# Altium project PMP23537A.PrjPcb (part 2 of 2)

## Sheet PMP23537A_PFC.SchDoc
size 431 x 279 mm; Date: Not shown in title block; ApprovedBy: Not shown in title block; CheckedBy: Not shown in title block; Author: Not shown in title block; CompanyName: Not shown in title block; Engineer: Not shown in title block; Organization: Not shown in title block; Address1: Not shown in title block; Address2: Not shown in title block; Address3: Not shown in title block; Address4: Not shown in title block; DocumentNumber: 1; Revision: Use project parameter SCH_Rev; SheetNumber: 1; SheetTotal: 2; PageSetup: Record=PageOptions¦CenterHorizontal=True¦CenterVertical=True¦PrintScale=1.00¦XCorrection=1.00¦YCorrection=1.00¦PrintKind=0¦BorderSize=5000000¦LeftOffset=0¦BottomOffset=0¦Orientation=2¦PaperLength=1000¦PaperWidth=1000¦Scale=100¦PaperSource=15¦PrintQuality=600¦MediaType=1¦DitherType=10¦PaperKind=Letter¦PrintScaleMode=1

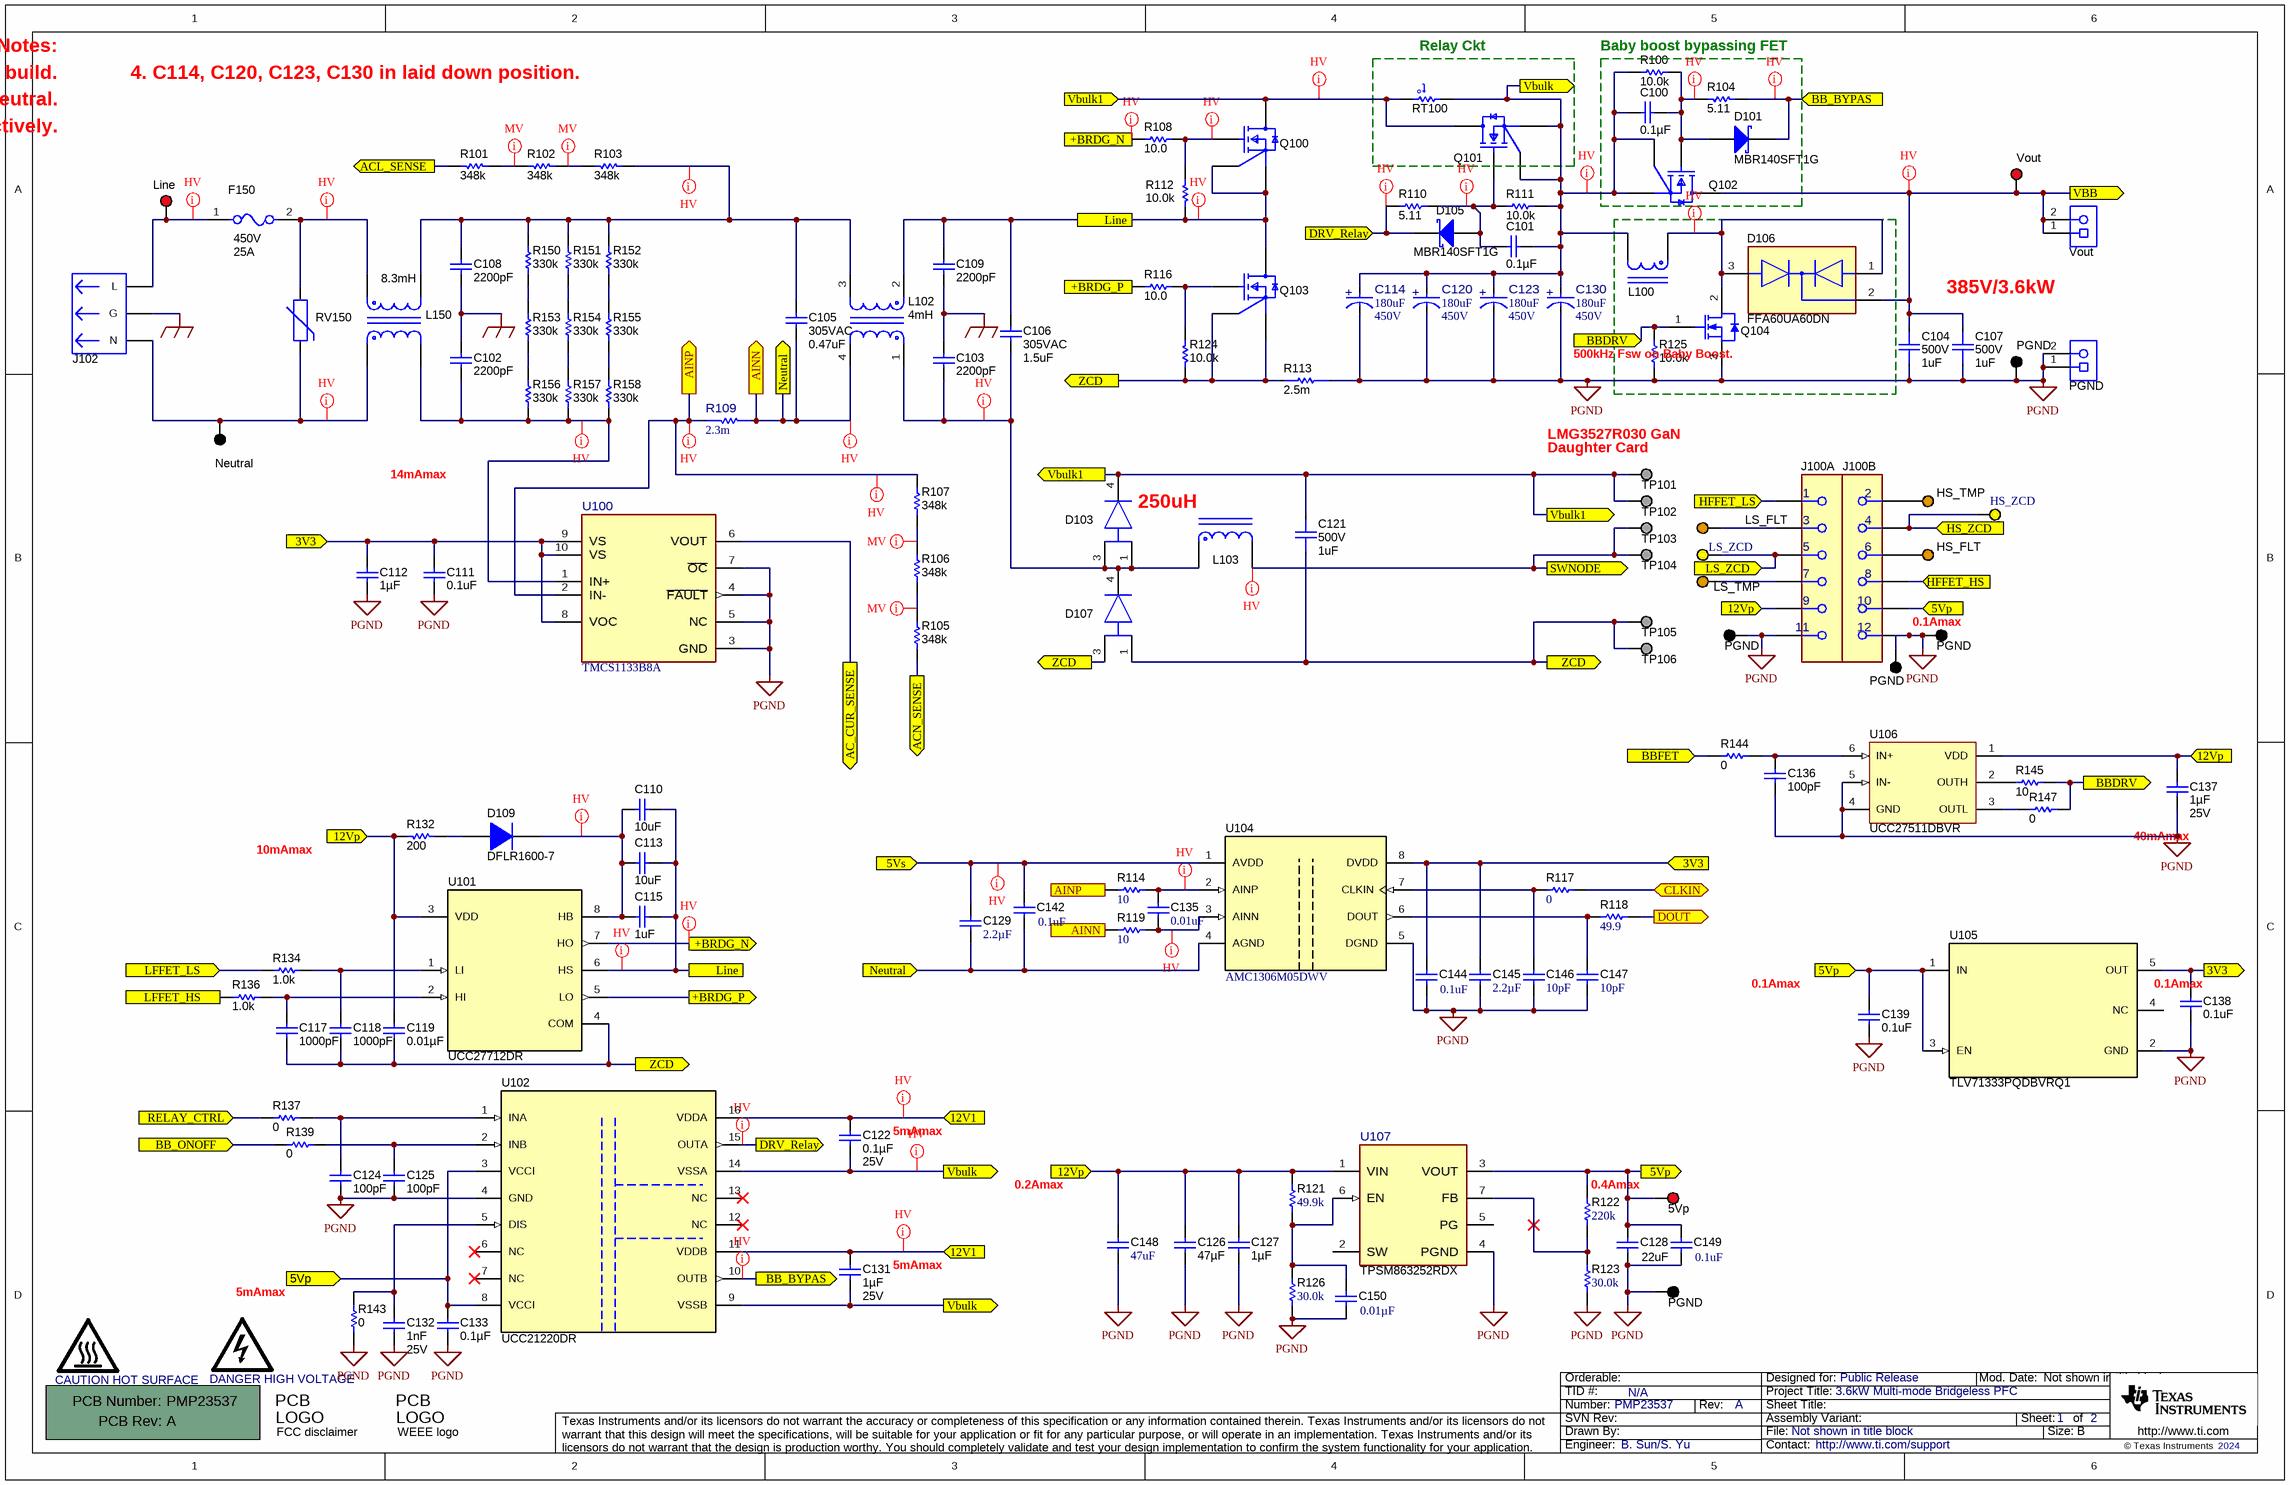
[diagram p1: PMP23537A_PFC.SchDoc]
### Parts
(Parts that share a designator on the sheet are numbered #1, #2 ... from top to bottom, then left to right.)
5Vp  5000  [Keystone5000]  (value not drawn)
!PCB100  Printed Circuit Board  (value not drawn)  (mechanical)
C100  ValueDisplayed: 0.1µF  [0603]  (hidden comment: 06033C104JAT2A)
C101  ValueDisplayed: 0.1µF  [0603]  (hidden comment: 06033C104JAT2A)
C102  ValueDisplayed: 2200pF  [E_900x700x900]  (hidden comment: DE6E3KJ222MN3A)
C103  ValueDisplayed: 2200pF  [E_900x700x900]  (hidden comment: DE6E3KJ222MN3A)
C104  VDC_V: 500V  ValueDisplayed: 1uF  [FP-B58031U5105M062_SMD2-MFG]  (hidden comment: B58031U5105M062)
C105  Value2: 305VAC  ValueDisplayed: 0.47uF  [B32923_16.5mm_10.5]  (hidden comment: B32923H3474K000)
C106  Value2: 305VAC  ValueDisplayed: 1.5uF  [B32923_29.5mm]  (hidden comment: B32923H3155K000)
C107  VDC_V: 500V  ValueDisplayed: 1uF  [FP-B58031U5105M062_SMD2-MFG]  (hidden comment: B58031U5105M062)
C108  ValueDisplayed: 2200pF  [E_900x700x900]  (hidden comment: DE6E3KJ222MN3A)
C109  ValueDisplayed: 2200pF  [E_900x700x900]  (hidden comment: DE6E3KJ222MN3A)
C110  ValueDisplayed: 10uF  [0805_HV]  (hidden comment: 0805YD106MAT2A)
C111  ValueDisplayed: 0.1uF  [0402]  (hidden comment: GRM155R70J104KA01D)
C112  ValueDisplayed: 1µF  [0603]  (hidden comment: GRM185R60J105KE26D)
C113  ValueDisplayed: 10uF  [0805_HV]  (hidden comment: 0805YD106MAT2A)
C114  ValueDisplayed: 180uF  VDC_V: 450V  [FP-450HXW180MEFR16X50_RADIAL-MFG]  (hidden comment: 450HXW180MEFR16X50)
C115  ValueDisplayed: 1uF  [0603]  (hidden comment: C1608X7R1E105K080AB)
C117  ValueDisplayed: 1000pF  [0603]  (hidden comment: 06035A102KAT2A)
C118  ValueDisplayed: 1000pF  [0603]  (hidden comment: 06035A102KAT2A)
C119  ValueDisplayed: 0.01µF  [0603]  (hidden comment: C0603X103K5RACTU)
C120  ValueDisplayed: 180uF  VDC_V: 450V  [FP-450HXW180MEFR16X50_RADIAL-MFG]  (hidden comment: 450HXW180MEFR16X50)
C121  VDC_V: 500V  ValueDisplayed: 1uF  [FP-B58031U5105M062_SMD2-MFG]  (hidden comment: B58031U5105M062)
C122  ValueDisplayed: 0.1µF  Value2: 25V  [0603]  (hidden comment: 06033C104JAT2A)
C123  ValueDisplayed: 180uF  VDC_V: 450V  [FP-450HXW180MEFR16X50_RADIAL-MFG]  (hidden comment: 450HXW180MEFR16X50)
C124  ValueDisplayed: 100pF  [0402]  (hidden comment: 0402YC101KAT2A)
C125  ValueDisplayed: 100pF  [0402]  (hidden comment: 0402YC101KAT2A)
C126  ValueDisplayed: 47µF  [1210_270]  (hidden comment: GRM32ER61C476KE15L)
C127  Cap_F: 1µF  [0805_HV]  (hidden comment: C0805C105K3RACTU)
C128  ValueDisplayed: 22uF  [0805_HV]  (hidden comment: CL21A226KQQNNNE)
C129  Cap_F: 2.2µF  [0603]  (hidden comment: GCM188R70J225KE22D)
C130  ValueDisplayed: 180uF  VDC_V: 450V  [FP-450HXW180MEFR16X50_RADIAL-MFG]  (hidden comment: 450HXW180MEFR16X50)
C131  ValueDisplayed: 1µF  Value2: 25V  [1206]  (hidden comment: C3216X7R1E105K085AA)
C132  Cap_F: 1nF  VDC_V: 25V  [0603]  (hidden comment: GRM188R71E102KA01D)
C133  ValueDisplayed: 0.1µF  [0402]  (hidden comment: 0402YC104KAT2A)
C135  ValueDisplayed: 0.01uF  [0402]  (hidden comment: GRM155R60J103KA01D)
C136  ValueDisplayed: 100pF  [0402]  (hidden comment: 0402YC101KAT2A)
C137  ValueDisplayed: 1µF  Value2: 25V  [1206]  (hidden comment: C3216X7R1E105K085AA)
C138  ValueDisplayed: 0.1uF  [0402]  (hidden comment: GRM155R70J104KA01D)
C139  ValueDisplayed: 0.1uF  [0402]  (hidden comment: GRM155R70J104KA01D)
C142  ValueDisplayed: 0.1uF  [0402]  (hidden comment: GRM155R70J104KA01D)
C144  ValueDisplayed: 0.1uF  [0402]  (hidden comment: GRM155R70J104KA01D)
C145  Cap_F: 2.2µF  [0603]  (hidden comment: GCM188R70J225KE22D)
C146  ValueDisplayed: 10pF  [0402]  (hidden comment: C0402C100C8GACTU)
C147  ValueDisplayed: 10pF  [0402]  (hidden comment: C0402C100C8GACTU)
C148  ValueDisplayed: 47uF  [1210_270]  (hidden comment: GRM32ER61C476KE15L)
C149  ValueDisplayed: 0.1uF  [0402]  (hidden comment: GRM155R70J104KA01D)
C150  ValueDisplayed: 0.01µF  [0402]  (hidden comment: C0402C103K4RACTU)
D101  MBR140SFT1G  [SOD-123FL]
D103  VS-15EVL06-M3/I  [FP-VS-15AWL06FN-M3_D-PAK (TO-252AA)-MFG]  (value not drawn)
D105  MBR140SFT1G  [SOD-123FL]
D106  FFA60UA60DN  [FP-FFA60UA60DN_SC-65-MFG]
D107  VS-15EVL06-M3/I  [FP-VS-15AWL06FN-M3_D-PAK (TO-252AA)-MFG]  (value not drawn)
D109  DFLR1600-7  [PowerDI123]
F150  VDC_V: 450V  Fuse Current: 25A  [FP-0525025.MXEP_vm_AXIAL-MFG]  (hidden comment: 0525025.MXEP_vm)
HS_FLT  5003  [Keystone5003]  (value not drawn)
HS_TMP  5003  [Keystone5003]  (value not drawn)
HS_ZCD  5004  [Keystone5004]  (value not drawn)
J100  HLE-106-02-G-DV-BE-A  [FP-HLE-106-02-G-DV-BE-A_HDR12-MFG]  (value not drawn)  (parts A,B of 2)
J102  703W-00/54  [CONN_QUALTEK-703W-0054]  (value not drawn)
L100  PAL6598.223NL  [FP-PAL6281.104NL_PTH_20MM5_11MM0-MFG]  (value not drawn)
L102  Ind_H: 4mH  [FP-PAC6270NL_PTH_TRANSFORMER_30MM0_19MM0-MFG]  (hidden comment: PAC6596NL)
L103  PAL6585.254NL  [FP-PAL6269NL_PTH_32MM0_27MM8-MFG]  (value not drawn)
L150  Ind_H: 8.3mH  [FP-PAC6280NL_PTH_25MM0_12MM5-MFG]  (hidden comment: PAC6597NL)
Line  L  [Keystone5000]  (value not drawn)
LOGO100  CAUTION HOT SURFACE  [IEC_HotSurface_Small]  (no BOM)
LOGO101  DANGER HIGH VOLTAGE  [IEC_HighVoltage_Small]  (no BOM)
Logo102  FCC disclaimer  [FCC_disclaimer]  (no BOM)
Logo103  WEEE logo  [WEEE_Minimum]  (no BOM)
LS_FLT  5003  [Keystone5003]  (value not drawn)
LS_TMP  5003  [Keystone5003]  (value not drawn)
LS_ZCD  5004  [Keystone5004]  (value not drawn)
Neutral  N  [Keystone5001]  (value not drawn)
PGND#2  1715721  [PhoenixContact_1715721]  (value not drawn)
PGND#3  N  [Keystone5001]  (value not drawn)
PGND#4  5001  [Keystone5001]  (value not drawn)
PGND#5  5001  [Keystone5001]  (value not drawn)
PGND#6  5001  [Keystone5001]  (value not drawn)
PGND#7  5001  [Keystone5001]  (value not drawn)
Q100  IPT60R022S7XTMA1  [FP-IPT60R080G7XTMA1_HSOF-8-MFG]  (value not drawn)
Q101  IPT60R022S7XTMA1  [FP-IPT60R080G7XTMA1_HSOF-8-MFG]  (value not drawn)
Q102  IPT60R022S7XTMA1  [FP-IPT60R080G7XTMA1_HSOF-8-MFG]  (value not drawn)
Q103  IPT60R022S7XTMA1  [FP-IPT60R080G7XTMA1_HSOF-8-MFG]  (value not drawn)
Q104  IPP60R060P7XKSA1  [TO-220AB]  (value not drawn)
R100  ValueDisplayed: 10.0k  [0603]  (hidden comment: CRCW060310K0FKEA)
R101  ValueDisplayed: 348k  [1206]  (hidden comment: RC1206FR-07348KL)
R102  ValueDisplayed: 348k  [1206]  (hidden comment: RC1206FR-07348KL)
R103  ValueDisplayed: 348k  [1206]  (hidden comment: RC1206FR-07348KL)
R104  ValueDisplayed: 5.11  [0603]  (hidden comment: CRCW06035R11FKEA)
R105  ValueDisplayed: 348k  [1206]  (hidden comment: RC1206FR-07348KL)
R106  ValueDisplayed: 348k  [1206]  (hidden comment: RC1206FR-07348KL)
R107  ValueDisplayed: 348k  [1206]  (hidden comment: RC1206FR-07348KL)
R108  ValueDisplayed: 10.0  [0603]  (hidden comment: CRCW060310R0FKEA)
R109  value 2.3m  [FP-CSS2H-2512K-2L30F_2512-MFG]  (hidden comment: CSS2H-2512K-2L30F)
R110  ValueDisplayed: 5.11  [1206]  (hidden comment: CRCW12065R11FKEA)
R111  ValueDisplayed: 10.0k  [0603]  (hidden comment: CRCW060310K0FKEA)
R112  ValueDisplayed: 10.0k  [0603]  (hidden comment: CRCW060310K0FKEA)
R113  value 2.5m  [FP-WSLP3921L1000FEA_3921-MFG]  (hidden comment: WSLP39212L500FEA)
R114  ValueDisplayed: 10  [0402]  (hidden comment: CRCW040210R0JNED)
R116  ValueDisplayed: 10.0  [0603]  (hidden comment: CRCW060310R0FKEA)
R117  ValueDisplayed: 0  [0402]  (hidden comment: CRCW04020000Z0ED)
R118  ValueDisplayed: 49.9  [0402]  (hidden comment: CRCW040249R9FKED)
R119  ValueDisplayed: 10  [0402]  (hidden comment: CRCW040210R0JNED)
R121  ValueDisplayed: 49.9k  [0402]  (hidden comment: CRCW040249K9FKED)
R122  ValueDisplayed: 220k  [0402]  (hidden comment: RC0402FR-07220KL)
R123  ValueDisplayed: 30.0k  [0402]  (hidden comment: CRCW040230K0FKED)
R124  ValueDisplayed: 10.0k  [0603]  (hidden comment: CRCW060310K0FKEA)
R125  ValueDisplayed: 10.0k  [0603]  (hidden comment: CRCW060310K0FKEA)
R126  ValueDisplayed: 30.0k  [0402]  (hidden comment: CRCW040230K0FKED)
R132  value 200  [0603]  (hidden comment: CRCW0603200RFKEA)
R134  value 1.0k  [0402]  (hidden comment: CRCW04021K00JNED)
R136  value 1.0k  [0402]  (hidden comment: CRCW04021K00JNED)
R137  ValueDisplayed: 0  [0402]  (hidden comment: CRCW04020000Z0ED)
R139  ValueDisplayed: 0  [0402]  (hidden comment: CRCW04020000Z0ED)
R143  ValueDisplayed: 0  [0603]  (hidden comment: CRCW06030000Z0EA)
R144  ValueDisplayed: 0  [0402]  (hidden comment: CRCW04020000Z0ED)
R145  ValueDisplayed: 10  [0603]  (hidden comment: CRCW060310R0JNEAHP)
R147  ValueDisplayed: 0  [0603]  (hidden comment: CRCW06030000Z0EA)
R150  ValueDisplayed: 330k  [1206]  (hidden comment: CRCW1206330KJNEA)
R151  ValueDisplayed: 330k  [1206]  (hidden comment: CRCW1206330KJNEA)
R152  ValueDisplayed: 330k  [1206]  (hidden comment: CRCW1206330KJNEA)
R153  ValueDisplayed: 330k  [1206]  (hidden comment: CRCW1206330KJNEA)
R154  ValueDisplayed: 330k  [1206]  (hidden comment: CRCW1206330KJNEA)
R155  ValueDisplayed: 330k  [1206]  (hidden comment: CRCW1206330KJNEA)
R156  ValueDisplayed: 330k  [1206]  (hidden comment: CRCW1206330KJNEA)
R157  ValueDisplayed: 330k  [1206]  (hidden comment: CRCW1206330KJNEA)
R158  ValueDisplayed: 330k  [1206]  (hidden comment: CRCW1206330KJNEA)
RT100  B59751B0120A070  [TDK_B751]  (value not drawn)
RV150  S10K275E2  [VAR_S10K275E2]  (value not drawn)
TP101  Suggest using a net name here  [Mill-Max_0312-0-15-15-34-27-10-0]  (value not drawn)
TP102  Suggest using a net name here  [Mill-Max_0312-0-15-15-34-27-10-0]  (value not drawn)
TP103  Suggest using a net name here  [Mill-Max_0312-0-15-15-34-27-10-0]  (value not drawn)
TP104  Suggest using a net name here  [Mill-Max_0312-0-15-15-34-27-10-0]  (value not drawn)
TP105  Suggest using a net name here  [Mill-Max_0312-0-15-15-34-27-10-0]  (value not drawn)
TP106  Suggest using a net name here  [Mill-Max_0312-0-15-15-34-27-10-0]  (value not drawn)
U100  TMCS1133B8A  [DVG0010A-MFG]
U101  UCC27712DR  [D0008A_N]
U102  UCC21220DR  [D0016B]
U104  AMC1306M05DWV  [DWV0008A]
U105  TLV71333PQDBVRQ1  [DBV0005A_N]
U106  UCC27511DBVR  [DBV0006A_N]
U107  TPSM863252RDX  [RDX0007A-MFG]
Vout#1  L  [Keystone5000]  (value not drawn)
Vout#2  1715721  [PhoenixContact_1715721]  (value not drawn)

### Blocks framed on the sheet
Relay Ckt: Q101 RT100
Baby boost bypassing FET: C100 D101 Q102 R100 R104
500kHz Fsw on Baby Boost.: D106 L100 Q104 R125

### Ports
3V3 (in), 3V3 (out), 5Vp (in), 5Vp (out), 5Vs (in), 12V1 (in), 12Vp (in), +BRDG_N (in), +BRDG_N (out), +BRDG_P (in), +BRDG_P (out), AC_CUR_SENSE (out), ACL_SENSE (out), ACN_SENSE (out), AINN (in), AINN (out), AINP (in), AINP (out), BB_BYPAS (in), BB_BYPAS (out), BB_ONOFF (in), BBDRV (in), BBDRV (out), BBFET (in), CLKIN (bidir), DOUT (out), DRV_Relay (in), DRV_Relay (out), HFFET_HS (in), HFFET_LS (in), HS_ZCD (in), LFFET_HS (in), LFFET_LS (in), Line, LS_ZCD (in), Neutral (in), Neutral (out), RELAY_CTRL (in), SWNODE (out), VBB (out), Vbulk1 (in), Vbulk1 (out), Vbulk (out), ZCD (out)

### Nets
PE: C102.2 C103.2 C108.1 C109.1 J102.3(G)
PGND: C104.1 C107.1 C111.2 C112.2 C114.1(CATHODE) C120.1(CATHODE) C123.1(CATHODE) C124.2 C125.2 C126.1 C127.2 C128.2 C130.1(CATHODE) C132.2 C133.2 C136.2 C137.2 C138.2 C139.2 C144.2 C145.2 C146.2 C147.2 C148.2 C149.2 C150.2 J100.11 J100.12 PGND#2.1 PGND#2.2 PGND#3.1 PGND#4.1 PGND#5.1 PGND#6.1 PGND#7.1 Q104.3(S) R113.1 R123.1 R125.1 R126.1 R143.1 U100.3(GND) U100.4(~{FAULT}) U100.5(NC) U100.7(~{OC}) U102.4(GND) U104.5(DGND) U105.2(GND) U106.4(GND) U106.5(IN-) U107.4(PGND)
3V3: C111.1 C112.1 C138.1 C144.1 C145.1 U100.8(VOC) U100.9(VS) U100.10(VS) U104.8(DVDD) U105.5(OUT) ; port 3V3
5Vp: 5Vp.1 C128.1 C133.1 C139.1 C149.1 J100.10 R122.2 U102.3(VCCI) U102.8(VCCI) U105.1(IN) U105.3(EN) U107.3(VOUT) ; port 5Vp
5Vs: C129.1 C142.1 U104.1(AVDD) ; port 5Vs
12V1: C122.2 C131.1 U102.11(VDDB) U102.16(VDDA) ; port 12V1
12Vp: C119.1 C126.2 C127.1 C137.1 C148.1 J100.9 R121.2 R132.2 U101.3(VDD) U106.1(VDD) U107.1(VIN) ; port 12Vp
+BRDG_N: R108.1 U101.7(HO) ; port +BRDG_N
+BRDG_P: R116.1 U101.5(LO) ; port +BRDG_P
AC_CUR_SENSE: U100.6(VOUT) ; port AC_CUR_SENSE
ACL_SENSE: R101.1 ; port ACL_SENSE
ACN_SENSE: R105.1 ; port ACN_SENSE
AINN: C105.1 C129.2 C142.2 L102.4 R109.2 R119.1 U104.4(AGND) ; port Neutral, port AINN
AINP: R107.2 R109.1 R114.1 U100.2(IN-) ; port AINP
BB_BYPAS: D101.1(K) R104.2 U102.10(OUTB) ; port BB_BYPAS
BB_ONOFF: R139.1 ; port BB_ONOFF
BBDRV: Q104.1(G) R125.2 R145.1 R147.2 ; port BBDRV
BBFET: R144.1 ; port BBFET
CLKIN: R117.2 ; port CLKIN
DOUT: R118.2 ; port DOUT
DRV_Relay: D105.1(K) R110.1 U102.15(OUTA) ; port DRV_Relay
HFFET_HS: J100.8 ; port HFFET_HS
HFFET_LS: J100.1 ; port HFFET_LS
HS_ZCD: HS_ZCD.1 J100.4 ; port HS_ZCD
LFFET_HS: R136.1 ; port LFFET_HS
LFFET_LS: R134.1 ; port LFFET_LS
Line: C106.2 C109.2 C110.2 C113.2 C115.1 L102.2 Q100.2(Driver_Source) Q100.3-4-5-6-7-8(Source) Q103.9(Drain) R112.1 U101.6(HS) ; port Line
LS_ZCD: J100.5 LS_ZCD.1 ; port LS_ZCD
RELAY_CTRL: R137.1 ; port RELAY_CTRL
SWNODE: L103.2 TP103.1 TP104.1 ; port SWNODE
VBB: C104.2 C107.2 D106.2(COMMON_CATHODE) Q102.9(Drain) Vout#1.1 Vout#2.1 Vout#2.2 ; port VBB
Vbulk: C100.2 C101.1 C114.2(ANODE) C120.2(ANODE) C122.1 C123.2(ANODE) C130.2(ANODE) C131.2 L100.2(F) Q101.2(Driver_Source) Q101.3-4-5-6-7-8(Source) Q102.2(Driver_Source) Q102.3-4-5-6-7-8(Source) R100.1 R111.2 RT100.1 U102.9(VSSB) U102.14(VSSA) ; port Vbulk
Vbulk1: C121.2 D103.4(Cathode) Q100.9(Drain) Q101.9(Drain) RT100.2 TP101.1 TP102.1 ; port Vbulk1
ZCD: C117.2 C118.2 C119.2 C121.1 D107.1(Anode) D107.3(Anode) Q103.2(Driver_Source) Q103.3-4-5-6-7-8(Source) R113.2 R124.1 TP105.1 TP106.1 U101.4(COM) ; port ZCD
NetC100_1: C100.1 D101.2(A) Q102.1(Gate) R100.2 R104.1
NetC101_2: C101.2 D105.2(A) Q101.1(Gate) R110.2 R111.1
NetC102_1: C102.1 L150.4 R156.1 R157.1 R158.1 U100.1(IN+)
NetC103_1: C103.1 C106.1 D103.1(Anode) D103.3(Anode) D107.4(Cathode) L102.1 L103.1
NetC105_2: C105.2 C108.2 L102.3 L150.3 R103.2 R150.2 R151.2 R152.2
NetC110_1: C110.1 C113.1 C115.2 D109.1(K) U101.8(HB)
NetC117_1: C117.1 R136.2 U101.2(HI)
NetC118_1: C118.1 R134.2 U101.1(LI)
NetC124_1: C124.1 R137.2 U102.1(INA)
NetC125_1: C125.1 R139.2 U102.2(INB)
NetC132_1: C132.1 R143.2 U102.5(DIS)
NetC135_1: C135.1 R114.2 U104.2(AINP)
NetC135_2: C135.2 R119.2 U104.3(AINN)
NetC136_1: C136.1 R144.2 U106.6(IN+)
NetC146_1: C146.1 R117.1 U104.7(CLKIN)
NetC147_1: C147.1 R118.1 U104.6(DOUT)
NetC150_1: C150.1 R121.1 R126.2 U107.6(EN)
NetD106_1: D106.1(1_ANODE) D106.3(2_ANODE) L100.1(S) Q104.2(D)
NetD109_2: D109.2(A) R132.1
NetF150_1: F150.1 J102.1(L) Line.1
NetF150_2: F150.2 L150.2 RV150.1
NetHS_FLT_1: HS_FLT.1 J100.6
NetHS_TMP_1: HS_TMP.1 J100.2
NetJ100_3: J100.3 LS_FLT.1
NetJ100_7: J100.7 LS_TMP.1
NetJ102_2: J102.2(N) L150.1 Neutral.1 RV150.2
NetQ100_1: Q100.1(Gate) R108.2 R112.2
NetQ103_1: Q103.1(Gate) R116.2 R124.2
NetR101_2: R101.2 R102.1
NetR102_2: R102.2 R103.1
NetR105_2: R105.2 R106.1
NetR106_2: R106.2 R107.1
NetR122_1: R122.1 R123.2 U107.7(FB)
NetR145_2: R145.2 U106.2(OUTH)
NetR147_1: R147.1 U106.3(OUTL)
NetR150_1: R150.1 R153.2
NetR151_1: R151.1 R154.2
NetR152_1: R152.1 R155.2
NetR153_1: R153.1 R156.2
NetR154_1: R154.1 R157.2
NetR155_1: R155.1 R158.2

Not connected (* = marked no-connect by the designer): U102 6(NC)* 7(NC)* 12(NC)* 13(NC)*; U105 4(NC); U107 2(SW) 5(PG)

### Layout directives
net class MV: NetR101_2, NetR102_2, NetR105_2, NetR106_2
net class HV: 5Vs, 12V1, +BRDG_N, AINN, AINP, BB_BYPAS, DRV_Relay, Line, NetC100_1, NetC101_2, NetC102_1, NetC103_1, NetC105_2, NetC110_1, NetC135_1, NetC135_2, NetD106_1, NetF150_1, NetF150_2, NetJ102_2, NetQ100_1, SWNODE, VBB, Vbulk, Vbulk1

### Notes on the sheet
- Notes:
- 1. Need to check part availability when request to build.
- 2. This board uses boot strap gate driver for LF FETs, does not support negative DC input on Neutral.
- 4. C114, C120, C123, C130 in laid down position.
- 3. 4x 180uF bulk cap is applied: C123 and C130 to be placed on top of C114 and C120, respectively.
- 385V/3.6kW
- (near TP101) LMG3527R030 GaN
- 14mAmax
- (near L103) 250uH
- (near TP101) Daughter Card
- (near PGND#5) 0.1Amax
- (near C137) 40mAmax
- (near R132) 10mAmax
- (near C139) 0.1Amax
- (near C138) 0.1Amax
- 5mAmax
- (near C148) 0.2Amax
- (near 5Vp) 0.4Amax
- (near R143) 5mAmax

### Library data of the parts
5Vp = 5000: Test Point, Miniature, Red, TH; Manufacturer: Keystone; CompType: Test Point Loop; ContactFinish: Silver; Green_Lifecycle: Active; Green_REACh: Passed
!PCB100 = CMP-0003618-2: Manufacturer: Any; PartNumber: PMP23537
C100 C101 C122 = 06033C104JAT2A: CAP, CERM, 0.1uF, 25V, +/-5%, X7R, 0603; Manufacturer: AVX; Polarized: N; CompType: Capacitor; U/M: EA; Cap_F: 0.0000001; Tolerance_%: 5; ESR_Ohm: 0.05; Value1: 0.05 ohm; VDC_V: 25; TaMin_C: -55; TaMax_C: 125
C102 C103 C108 C109 = DE6E3KJ222MN3A: CAP, CERM, 2200 pF, 300 V, +/- 20%, E, TH, 2- Leads, Body 9x7mm, Pin Spacing 7.5mm; Manufacturer: MuRata; Polarized: N; CompType: Capacitor; Value: 2200pF; U/M: EA; Cap_F: 0.0000000022; Tolerance_%: 20; Value1: Unknown; VDC_V: 300; Value2: 300V; TaMin_C: -40; TaMax_C: 125; Cap_Case: 9x7x9mm; SizeArea_mm2: 63; SizeAreaWB_mm2: 99; SizeX_mm: 9; SizeY_mm: 7; SizeZ_mm: 12; AEC Category: Q200
C104 C107 C121 = CMP-0091050-1: TDK 1µF Multilayer Ceramic Capacitor MLCC 500V dc ±20% SMD; AEC Grade: Grade 0; AEC Qualified: Yes; SizeZ_mm: 4.5mm
C105 = CMP-0012429-3: CAP FILM 0.47UF 10% 630VDC RAD; Manufacturer: TDK; Polarized: N; SizeAreaWB_mm2: 356.25; Value1: Unknown; TaMax_C: 110°C; Tolerance_%: 20%; SizeZ_mm: 16.5; SizeX_mm: 26.5; SizeY_mm: 10.5; SizeArea_mm2: 278.25; CompType: Capacitor; Cap_F: 470nF; VDC_V: 630V; AEC Category: Q200
C106 = CMP-0012424-1: CAP FILM 1.5UF 10% 630VDC RADIAL; Manufacturer: TDK; Polarized: N; SizeAreaWB_mm2: 470.25; Value1: Unknown; U/M: EA; TaMax_C: 110°C; Tolerance_%: 20%; SizeZ_mm: 29.5; SizeX_mm: 26.5; SizeY_mm: 14.5; SizeArea_mm2: 384.25; CompType: Capacitor; Cap_F: 1.5µF; VDC_V: 630V; AEC Category: Q200
C110 C113 = 0805YD106MAT2A: CAP, CERM, 10uF, 16V, +/-20%, X5R, 0805; Manufacturer: AVX; Polarized: N; CompType: Capacitor; U/M: EA; Cap_F: 0.00001; Tolerance_%: 20; Value1: Unknown; VDC_V: 16; TaMin_C: -55; TaMax_C: 85; Cap_Case: 0805
C111 C138 C139 = GRM155R70J104KA01D: CAP, CERM, 0.1uF, 6.3V, +/-10%, X7R, 0402; Manufacturer: MuRata; Polarized: N; CompType: Capacitor; U/M: EA; Cap_F: 0.0000001; Tolerance_%: 10; Value1: Unknown; VDC_V: 6.3; TaMin_C: -55; TaMax_C: 125
C112 = GRM185R60J105KE26D: CAP, CERM, 1uF, 6.3V, +/-10%, X5R, 0603; Manufacturer: MuRata; Polarized: N; CompType: Capacitor; U/M: EA; Cap_F: 0.000001; Tolerance_%: 10; Value1: Unknown; VDC_V: 6.3; TaMin_C: -55; TaMax_C: 85
C114 C120 C123 C130 = CMP-0098127-1: 180 µF 450 V Aluminum Electrolytic Capacitors Radial, Can 3000 Hrs @ 105°C; Manufacturer: Rubycon; Tolerance_%: 20%; SizeZ_mm: 52mm; Life: 3000Hours; Dissipation Factor: 25%; AEC Qualified: No; Cap_F: 180µF; Value: 180µF; Leakage Current: 853.8uA; IRMS_A: 1.15A
C115 = C1608X7R1E105K080AB: CAP, CERM, 1uF, 25V, +/-10%, X7R, 0603; Manufacturer: TDK; Polarized: N; CompType: Capacitor; U/M: EA; Cap_F: 0.000001; Tolerance_%: 10; Value1: Unknown; VDC_V: 25; TaMin_C: -55; TaMax_C: 125
C117 C118 = 06035A102KAT2A: CAP, CERM, 1000 pF, 50 V, +/- 10%, C0G/NP0, 0603; Manufacturer: AVX; Polarized: N; CompType: Capacitor; Value: 1000pF; U/M: EA; Cap_F: 0.000000001; Tolerance_%: 10; ESR_ohm: 0.048; Value1: 0.048 ohm; VDC_V: 50; Value2: 50V; TaMin_C: -55; TaMax_C: 125; SizeArea_mm2: 1.28; SizeAreaWB_mm2: 4.68; SizeX_mm: 1.6; SizeY_mm: 0.8; SizeZ_mm: 1; AEC Category: Q200
C119 = C0603X103K5RACTU: CAP, CERM, 0.01uF, 50V, +/-10%, X7R, 0603; Manufacturer: Kemet; Polarized: N; CompType: Capacitor; U/M: EA; Cap_F: 0.00000001; Tolerance_%: 10; Value1: Unknown; VDC_V: 50; TaMin_C: -55; TaMax_C: 125
C124 C125 C136 = 0402YC101KAT2A: CAP, CERM, 100 pF, 16 V,+/- 10%, X7R, 0402; Manufacturer: AVX; Polarized: N; CompType: Capacitor; Value: 100pF; U/M: EA; Cap_F: 0.0000000001; Tolerance_%: 10; VDC_V: 16; Value2: 16V; TaMin_C: -55; TaMax_C: 125; SizeArea_mm2: 0.5; SizeAreaWB_mm2: 3; SizeX_mm: 1; SizeZ_mm: 0.6; AEC Category: Q200
C126 = GRM32ER61C476KE15L: CAP, CERM, 47 µF, 16 V, +/- 10%, X5R, 1210; Manufacturer: MuRata; Polarized: N; CompType: Capacitor; Value: 47uF; U/M: EA; Cap_F: 0.000047; Tolerance_%: 10; Value1: Unknown; VDC_V: 16; TaMin_C: -55; TaMax_C: 85; Cap_Case: 1210; SizeArea_mm2: 8; SizeAreaWB_mm2: 14.7; SizeX_mm: 3.2; SizeY_mm: 2.5; SizeZ_mm: 2.7; AEC Category: Q200
C127 = CMP-0007728-2: CAP, CERM, 1 uF, 25 V, +/- 10%, X7R, 0805; Manufacturer: Kemet; TaMin_C: -55°C; Polarized: N; SizeAreaWB_mm2: 6.75; Value1: Unknown; U/M: EA; Value: 1uF; TaMax_C: 125°C; SizeZ_mm: 1.45; SizeX_mm: 2; SizeY_mm: 1.25; Cap_Case: 0805; Value2: 25V; SizeArea_mm2: 2.5; AEC Category: Q200
C128 = CMP-0007989-2: CAP, CERM, 22 uF, 6.3 V, +/- 10%, X5R, 0805; Manufacturer: Samsung Electro-Mechanics; TaMin_C: -55°C; Polarized: N; SizeAreaWB_mm2: 6.75; Value1: Unknown; U/M: EA; Value: 22uF; TaMax_C: 85°C; SizeZ_mm: 1.45; SizeX_mm: 2; SizeY_mm: 1.25; Cap_Case: 0805; Value2: 6.3V; SizeArea_mm2: 2.5; Cap_F: 22µF; AEC Category: Q200
C129 C145 = CMP-0007134-5: CAP, CERM, 2.2 uF, 6.3 V, +/- 10%, X7R, AEC-Q200 Grade 1, 0603; Manufacturer: MuRata; TaMin_C: -55°C; Polarized: N; SizeAreaWB_mm2: 4.68; Value1: Unknown; U/M: EA; Value: 2.2uF; TaMax_C: 125°C; SizeZ_mm: 1; SizeX_mm: 1.6; SizeY_mm: 0.8; Value2: 6.3V; SizeArea_mm2: 1.28; AEC Qualified: Y; AEC Category: Q200
C131 C137 = C3216X7R1E105K085AA: CAP, CERM, 1 µF, 25 V,+/- 10%, X7R, 1206; Manufacturer: TDK; Polarized: N; CompType: Capacitor; Value: 1uF; U/M: EA; Cap_F: 0.000001; Tolerance_%: 10; ESR_ohm: 0.01; Value1: 0.01 ohm; VDC_V: 25; TaMin_C: -55; TaMax_C: 125; SizeArea_mm2: 5.12; SizeAreaWB_mm2: 10.92; SizeX_mm: 3.2; SizeY_mm: 1.6; SizeZ_mm: 1.35; AEC Category: Q200; Green_Lifecycle: NRND; Green_REACh: Passed
C132 = CMP-0007402-1: CAP, CERM, 1000 pF, 25 V, +/- 10%, X7R, 0603; Manufacturer: MuRata; TaMin_C: -55°C; Polarized: N; SizeAreaWB_mm2: 4.68; Value1: Unknown; U/M: EA; Value: 1000pF; TaMax_C: 125°C; SizeZ_mm: 1; SizeX_mm: 1.6; SizeY_mm: 0.8; SizeArea_mm2: 1.28; AEC Category: Q200
C133 = 0402YC104KAT2A: CAP, CERM, 0.1 µF, 16 V,+/- 10%, X7R, 0402; Manufacturer: AVX; Polarized: N; CompType: Capacitor; Value: 0.1uF; U/M: EA; Cap_F: 0.0000001; Tolerance_%: 10; VDC_V: 16; Value2: 16V; TaMin_C: -55; TaMax_C: 125; SizeArea_mm2: 0.5; SizeAreaWB_mm2: 3; SizeX_mm: 1; SizeZ_mm: 0.6; AEC Category: Q200; Green_Lifecycle: Active; Green_REACh: Passed
C135 = CMP-0006530-2: CAP, CERM, 0.01 uF, 6.3 V, +/- 10%, X5R, 0402; Manufacturer: MuRata; TaMin_C: -55°C; Polarized: N; SizeAreaWB_mm2: 3; Value1: Unknown; U/M: EA; Value: 0.01uF; TaMax_C: 85°C; SizeZ_mm: 0.6; SizeX_mm: 1; SizeY_mm: 0.5; Value2: 6.3V; Cap_F: 10nF; AEC Category: Q200
C142 C144 C149 = CMP-0006623-2: CAP, CERM, 0.1 uF, 6.3 V, +/- 10%, X7R, 0402; Manufacturer: MuRata; TaMin_C: -55°C; Polarized: N; SizeAreaWB_mm2: 3; Value1: Unknown; U/M: EA; Value: 0.1uF; TaMax_C: 125°C; SizeZ_mm: 0.6; SizeX_mm: 1; SizeY_mm: 0.5; Value2: 6.3V; Cap_F: 100nF; AEC Category: Q200
C146 C147 = CMP-0064914-1: CAP, CERM, 10 pF, 10 V,+/- 2.5%, C0G/NP0, 0402; Manufacturer: Kemet; TaMin_C: -55°C; Polarized: N; SizeAreaWB_mm2: 3; Value1: Unknown; U/M: EA; Value: 10pF; TaMax_C: 125°C; SizeZ_mm: 0.6; SizeX_mm: 1; SizeY_mm: 0.5; Value2: 10V; AEC Category: Q200
C148 = CMP-0009211-1: CAP, CERM, 47 uF, 16 V, +/- 10%, X5R, 1210; Manufacturer: MuRata; TaMin_C: -55°C; Polarized: N; SizeAreaWB_mm2: 14.7; Value1: Unknown; U/M: EA; Value: 47uF; TaMax_C: 85°C; SizeZ_mm: 2.7; SizeX_mm: 3.2; SizeY_mm: 2.5; Cap_Case: 1210; Value2: 16V; SizeArea_mm2: 8; Cap_F: 47µF; AEC Category: Q200
C150 = CMP-0078218-1: CAP, CERM, 0.01 µF, 16 V,+/- 10%, X7R, 0402; Manufacturer: Kemet; TaMin_C: -55°C; Polarized: N; Green_Lifecycle: Active; SizeAreaWB_mm2: 3; Green_REACh: Passed; U/M: EA; Value: 0.01uF; TaMax_C: 125°C; SizeZ_mm: 0.6; SizeX_mm: 1; SizeY_mm: 0.5; Value2: 16V; Cap_F: 10nF; AEC Category: Q200
D101 D105 = CMP-0028548-2: Diode, Schottky, 40 V, 1 A, SOD-123FL; Manufacturer: ON Semiconductor; SizeZ_mm: 0.98; Vf_V: 5.5dV; AEC Category: Q101; Green_REACh: Passed; SizeArea_mm2: 5.94; Vr_V: 40V; TJmax_C: 125°C; RJC_CperW: 26; Value1: 1A; SizeY_mm: 1.65; SizeX_mm: 3.6; Value: 40V; Value2: 0.55V; SizeAreaWB_mm2: 12.19; Green_Lifecycle: Active
D103 D107 = CMP-0086603-1: DIODE GEN PURPOSE 600V SLIMDPAK; Manufacturer: Vishay; TJmax_C: 175°C; SizeZ_mm: 2.52mm; AEC Qualified: No
D106 = CMP-0090872-1: Diode Array 1 Pair Common Cathode Standard 600V 30A Through Hole TO-3P-3, SC-65-3; Manufacturer: ON Semiconductor; Peak Reverse Current: 100uA; SizeZ_mm: 23.8mm; AEC Qualified: No; TJmax_C: 175°C; Max Surge Forward Current: 180A; Standoff Height: 3.3mm
D109 = CMP-0076978-2: Diode, Standard Recovery Rectifier, 600 V, 1 A, PowerDI123; Manufacturer: Diodes Inc.; AEC Category: Q101; SizeAreaWB_mm2: 13.066; SizeY_mm: 1.78; Value2: 1.1V; TJmax_C: 150°C; Green_Lifecycle: Not Set; Value1: 1A; Value: 600V; SizeZ_mm: 0.98; SizeX_mm: 3.7; SizeArea_mm2: 6.586; Green_REACh: Incomplete
F150 = CMP-4956-0000-1: 25A AC 450V DC Fuse Cartridge, Ceramic Through Hole 3AB, 3AG, 1/4" x 1-1/4" (Axial); Manufacturer: Littelfuse; AEC Grade: NA; Fuse Interrupt Dc Current: 10000A; AEC Qualified: No; Res_ohm: 3.8mΩ; MeltingTyp: 320A2Sec; Interrupt_DC: 10kA
HS_FLT HS_TMP LS_FLT LS_TMP = 5003: Test Point, Miniature, Orange, TH; Manufacturer: Keystone; CompType: Test Point Loop; ContactFinish: Silver; Green_Lifecycle: Active; Green_REACh: Passed
HS_ZCD LS_ZCD = CMP-0055141-1: Test Point, Miniature, Yellow, TH; Manufacturer: Keystone; CNHeader: FALSE; Green_Lifecycle: Active; Green_REACh: Passed; ContactFinish: Silver; CT: TRUE
J100 = CMP-0089984-1: 12 Position Receptacle, Bottom Entry Connector  Surface Mount; Manufacturer: Samtec; Current_A: 4.1A; Conn Orientation: Vertical; DUT-Pitch_mm: 2.54mm; Conn Gender: Female; SizeZ_mm: 3.79mm; Is Female: yes; AEC Qualified: No; ContactFinish: Gold,Nickel; Voltage_V: 400V; Row_Count: 2
J102 = 703W-00/54: AC Receptacle, 10A 250VAC; Manufacturer: Qualtek Electronics Corporation; SymbolCreator: a0799628; CompType: Connector; U/M: EA
L100 = CMP-0091020-1: Inductor Buck/Boost, Toroid, TH, 22uH 15% 8A; Manufacturer: Pulse Electronics; DCR_ohm: 1.08d; AEC Qualified: No; SizeZ_mm: 22.5mm; Test Frequency: 100kHz; Ind_H: 100µH
L102 = CMP-0091106-1: IND, CUR-SENSE, 4MH, 20A, TOR, TH; Manufacturer: Pulse Electronics; DCR_ohm: 6m; Voltage_Isolation_Vrms: 1500VDC; AEC Qualified: No; SizeZ_mm: 32mm; Rsec1_ohm: 6mΩ; Ns1toNp: 1:1
L103 = CMP-0091118-1: Inductor Power 250uH T27 THT; Manufacturer: Pulse Electronics; Tolerance_%: 15%; Test Frequency: 100kHz; Ind_H: 250µH; DCR_ohm: 0.075; SizeZ_mm: 30.5mm
L150 = CMP-0091125-1: INDUCTOR CUR-SENSE 8.3mH TOR TH; Manufacturer: Pulse Electronics; Tolerance_%: 30%; AEC Qualified: No; SizeZ_mm: 24.5mm; Test Frequency: 10kHz; DCR_ohm: 0.012
Line Vout#1 = 5000: Test Point, Miniature, Red, TH; Manufacturer: Keystone; CompType: Test Point Loop; U/M: EA
LOGO100 = CMP-0074837-1: IEC 61010-1 Hot Surface Warning; Library Reference: IEC_HotSurface; SymbolCreator: a0412235
LOGO101 = CMP-0074835-1: IEC 61010-1 High Voltage Warning; Library Reference: IEC_HighVoltage; SymbolCreator: a0412235
Logo102 = CMP-0074847-1: FCC_disclaimer; Library Reference: Logo
Logo103 = CMP-0074769-1
Neutral PGND#3 = 5001: Test Point, Miniature, Black, TH; Manufacturer: Keystone; CompType: Test Point Loop; U/M: EA
PGND#2 Vout#2 = CMP-0055471-1: Terminal Block, 5.08 mm, 2x1, TH; Manufacturer: Phoenix Contact; Cert_VDE: Y; CNHeader: FALSE; Current_A: 17.5A; Green_Lifecycle: Not Set; Gender: Female; Cert_CULUS: N; Green_REACh: Incomplete; Voltage_V: 400V; Row_Count: 1; Pitch_mm: 5.08; ContactFinish: Tin; CT: TRUE
PGND#4-PGND#7 = 5001: Test Point, Miniature, Black, TH; Manufacturer: Keystone; CompType: Test Point Loop; ContactFinish: Silver; Green_Lifecycle: Active; Green_REACh: Passed
Q100-Q103 = CMP-0086487-1: N-Channel 600V 23A (Tc) 390W (Tc) Surface Mount PG-HSOF-8-2; Manufacturer: Infineon; VdsMax_V: 650V; IdsMax_A: 29A; Vgs_V: 20V; AEC Qualified: No; ChMode: False; SizeZ_mm: 2.4mm
Q104 = CMP-0001223-3: MOSFET N-CH 600V 48A TO220-3; Alternate Manufacturer: None; Manufacturer: Infineon Technologies; ChType: N; AEC Category: Q101; U/M: EA
R100 R111 R112 R124 R125 = CRCW060310K0FKEA: RES, 10.0 k, 1%, 0.1 W, 0603; Manufacturer: Vishay-Dale; CompType: Resistor; Value: 10.0k; Res_ohm: 10000; Value_Code: 10k0; Tolerance_%: 1; Power_W: 0.1; Value2: 0.1W; VDC_V: 75; TempCo: 100 ppm/C; SizeArea_mm2: 1.28; SizeX_mm: 1.6; SizeY_mm: 0.8; EIA_Code: E96; U/M: EA; AEC Category: Q200; Green_Lifecycle: Active; Green_REACh: Passed
R101-R103 R105-R107 = CMP-0018215-2: RES, 348 k, 1%, 0.25 W, 1206; Manufacturer: Yageo America; Power_W: 250mW; TempCo: 100 ppm/C; U/M: EA; Value: 348k; EIA_Code: E96; SizeX_mm: 3.2; SizeY_mm: 1.6; SizeZ_mm: 1.35; Value2: 0.25W; SizeArea_mm2: 5.12; VDC_V: 200V; AEC Category: Q200
R104 = CRCW06035R11FKEA: RES, 5.11, 1%, 0.1 W, 0603; Manufacturer: Vishay-Dale; CompType: Resistor; Value: 5.11; Value_Code: 5R11; Tolerance_%: 1; Power_W: 0.1; Value2: 0.1W; VDC_V: 75; TempCo: 100 ppm/C; SizeArea_mm2: 1.28; SizeX_mm: 1.6; SizeY_mm: 0.8; EIA_Code: E96; U/M: EA; AEC Category: Q200; Green_Lifecycle: Active; Green_REACh: Passed
R108 R116 = CRCW060310R0FKEA: RES, 10.0, 1%, 0.1 W, 0603; Manufacturer: Vishay-Dale; CompType: Resistor; Value: 10.0; Res_ohm: 10; Value_Code: 10R0; Tolerance_%: 1; Power_W: 0.1; Value2: 0.1W; VDC_V: 75; TempCo: 100 ppm/C; SizeArea_mm2: 1.28; SizeX_mm: 1.6; SizeY_mm: 0.8; EIA_Code: E96; U/M: EA; AEC Category: Q200; Green_Lifecycle: Active; Green_REACh: Passed
R109 = CMP-21571-0000-1: Res Metal Strip 2512 2.3MilliOhm 1% 5W ±75ppm/°C Molded T/R; Manufacturer: Bourns; AEC Grade: Grade 0; AEC Qualified: Yes; SizeZ_mm: 1.09mm
R110 = CRCW12065R11FKEA: RES, 5.11, 1%, 0.25 W, 1206; Manufacturer: Vishay-Dale; CompType: Resistor; Value: 5.11; Value_Code: 5R11; Tolerance_%: 1; Power_W: 0.25; Value2: 0.25W; VDC_V: 200; TempCo: 100 ppm/C; SizeArea_mm2: 5.12; SizeX_mm: 3.2; SizeY_mm: 1.6; SizeZ_mm: 1.35; EIA_Code: E96; U/M: EA; AEC Category: Q200
R113 = CMP-0092403-1: RES 0.0025 OHM 1% 5W 3921; Manufacturer: Vishay; AEC Grade: Grade 0; SizeZ_mm: 0.081inch; TempCo: 350ppm/°C; AEC Qualified: Yes
R114 R119 = CMP-0026827-3: RES, 10, 5%, 0.063 W, AEC-Q200 Grade 0, 0402; Manufacturer: Vishay-Dale; Power_W: 63mW; TempCo: 200 ppm/C; Value_Code: 10R0; Value: 10; EIA_Code: E24; SizeX_mm: 1; SizeY_mm: 0.5; SizeZ_mm: 0.6; Value2: 0.063W; AEC Qualified: Y; VDC_V: 50V; AEC Category: Q200; AEC Grade: 0
R117 = CMP-0026822-3: RES, 0, 5%, 0.063 W, AEC-Q200 Grade 0, 0402; Manufacturer: Vishay-Dale; Power_W: 63mW; TempCo: 200 ppm/C; Value_Code: 0000; Value: 0; EIA_Code: E24; SizeX_mm: 1; SizeY_mm: 0.5; SizeZ_mm: 0.6; Value2: 0.063W; AEC Qualified: Y; VDC_V: 50V; AEC Category: Q200
R118 = CMP-0026404-1: RES, 49.9, 1%, 0.063 W, 0402; Manufacturer: Vishay-Dale; Power_W: 63mW; TempCo: 100 ppm/C; Value_Code: 49R9; U/M: EA; Value: 49.9; EIA_Code: E96; SizeX_mm: 1; SizeY_mm: 0.5; SizeZ_mm: 0.6; Value2: 0.063W; VDC_V: 50V; AEC Category: Q200
R121 = CMP-0026403-2: RES, 49.9 k, 1%, 0.063 W, AEC-Q200 Grade 0, 0402; Manufacturer: Vishay-Dale; Power_W: 63mW; TempCo: 100 ppm/C; Value_Code: 49k9; Value: 49.9k; EIA_Code: E96; SizeX_mm: 1; SizeY_mm: 0.5; SizeZ_mm: 0.6; Value2: 0.063W; AEC Qualified: Y; VDC_V: 50V; AEC Category: Q200; AEC Grade: 0
R122 = CMP-0026728-1: RES, 220 k, 1%, 0.0625 W, 0402; Manufacturer: Yageo America; Power_W: 62.5mW; TempCo: 100 ppm/C; U/M: EA; Value: 220k; SizeX_mm: 1; SizeY_mm: 0.5; SizeZ_mm: 0.6; AEC Qualified: N; VDC_V: 50V; AEC Category: Q200
R123 R126 = CMP-0078244-2: RES, 30.0 k, 1%, 0.063 W, AEC-Q200 Grade 0, 0402; Manufacturer: Vishay-Dale; Power_W: 63mW; Green_Lifecycle: Active; TempCo: 100 ppm/C; Value_Code: 30k0; Green_REACh: Passed; Value: 30.0k; Res_ohm: 30k; SizeX_mm: 1; SizeY_mm: 0.5; SizeZ_mm: 0.6; Value2: 0.063W; AEC Qualified: Y; VDC_V: 50V; AEC Grade: 0; AEC Category: Q200
R132 = CRCW0603200RFKEA: RES, 200 ohm, 1%, 0.1W, 0603; Manufacturer: Vishay-Dale; CompType: Resistor; Value_Code: 200R; Tolerance_%: 1; Power_W: 0.1; VDC_V: 75; TempCo: 100 ppm/C; EIA_Code: E96; U/M: EA
R134 R136 = CRCW04021K00JNED: RES, 1.0k ohm, 5%, 0.063W, 0402; Manufacturer: Vishay-Dale; CompType: Resistor; Res_ohm: 1000; Value_Code: 1k00; Tolerance_%: 5; Power_W: 0.063; VDC_V: 50; TempCo: 200 ppm/C; EIA_Code: E24; U/M: EA
R137 R139 R144 = CRCW04020000Z0ED: RES, 0, 5%, 0.063 W, 0402; Manufacturer: Vishay-Dale; CompType: Resistor; Value: 0; Value_Code: 0000; Tolerance_%: 5; Power_W: 0.063; Value2: 0.063W; VDC_V: 50; TempCo: 200 ppm/C; SizeArea_mm2: 0.5; SizeX_mm: 1; SizeZ_mm: 0.6; EIA_Code: E24; U/M: EA; AEC Category: Q200; Green_Lifecycle: Active; Green_REACh: Passed
R143 R147 = CRCW06030000Z0EA: RES, 0, 5%, 0.1 W, 0603; Manufacturer: Vishay-Dale; CompType: Resistor; Value: 0; Value_Code: 0000; Tolerance_%: 5; Power_W: 0.1; Value2: 0.1W; VDC_V: 75; TempCo: 200 ppm/C; EIA_Code: E24; U/M: EA; AEC Category: Q200
R145 = CRCW060310R0JNEAHP: RES, 10, 5%, 0.25 W, 0603; Manufacturer: Vishay-Dale; CompType: Resistor; Value: 10; Value_Code: 10R0; Tolerance_%: 5; Power_W: 0.25; Value2: 0.25W; VDC_V: 75; TempCo: 200 ppm/C; EIA_Code: E24; U/M: EA
R150-R158 = CRCW1206330KJNEA: RES, 330 k, 5%, 0.25 W, 1206; Manufacturer: Vishay-Dale; CompType: Resistor; Value: 330k; Res_ohm: 330000; Tolerance_%: 5; Power_W: 0.25; Value2: 0.25W; VDC_V: 200; TempCo: 200 ppm/C; SizeArea_mm2: 5.12; SizeX_mm: 3.2; SizeY_mm: 1.6; SizeZ_mm: 1.35; EIA_Code: E24; U/M: EA; AEC Category: Q200
RT100 = B59751B0120A070: Thermistor PTC, 50 ohm, 25%, D12.5xH16.5mm; Manufacturer: TDK; CompType: ThermistorNTC; Value: 50 ohm; Tolerance_%: 25; TaMin_C: -40; TaMax_C: 125; U/M: EA
RV150 = S10K275E2: Varistor 275V RMS 10MM Radial, TH; Manufacturer: EPCOS Inc; SymbolCreator: a0412235
TP101-TP106 = 0312-0-15-15-34-27-10-0: Pin Receptacle, .032-.046" .075" Dia, Gold, TH; Manufacturer: Mill-Max; Gender: Female
U100 = CMP-0097984-1: Part Number: TMCS1133B1QDVGR; Manufacturer: Texas Instruments; Standoff Height: 0.1mm; SizeZ_mm: 2.65mm
U101 = CMP-0013005-2: 620-V High-Side Low-Side Gate Driver with 2.5A Peak Output and RobustDrive, D0008A (SOIC-8); Manufacturer: Texas Instruments; SizeX_mm: 4.9; SizeY_mm: 6.2; CompType: IC; SizeZ_mm: 1.75; SizeArea_mm2: 30.38; SizeAreaWB_mm2: 56.58; U/M: EA
U102 = CMP-0077646-2: 4-A, 6-A, 3.0-kVRMS Isolated Dual-Channel Gate Driver, D0016B (SOIC-16); Alternate Manufacturer: Texas Instruments; SizeAreaWB_mm2: 95.2; SizeZ_mm: 1.75; SizeX_mm: 6.0; SizeY_mm: 9.9; SizeArea_mm2: 59.4; CompType: IC; AEC Qualified: N; AEC Category: Q200; Rating: Catalog
U104 = CMP-0085668-1: Small Reinforced Isolated Modulator With +/-50mV Input and CMOS Interface, DWV0008A (SOIC-8); Manufacturer: Texas Instruments; Alternate PartNumber: AMC1306M05DWVR; SizeY_mm: 5.85; Rating: Catalog; CompType: IC; SizeZ_mm: 2.8; AEC Qualified: N; SizeArea_mm2: 67.275; AEC Category: Q200; SizeAreaWB_mm2: 105.975; SizeX_mm: 11.5
U105 = TLV71333PQDBVRQ1: Capacitor-Free, 150-mA, Low-Dropout Regulator with Foldback Current Limit for Portable Devices, DBV0005A; Manufacturer: Texas Instruments; SymbolCreator: Altium; SizeArea_mm2: 8.12; SizeAreaWB_mm2: 14.82; SizeX_mm: 2.8; SizeY_mm: 2.9; SizeZ_mm: 1.45; CompType: IC; U/M: EA
U106 = UCC27511DBVR: Single-Channel High-Speed Low-Side Gate Driver (with 4-A Peak Source and 8-A Peak Sink), DBV0006A; Alternate PartNumber: UCC27511DBVT; Manufacturer: Texas Instruments; SymbolCreator: a0411947; CompType: IC; U/M: EA
U107 = CMP-0097277-1: 3V to 16 V Input, 3-A Synchronous Step-Down Voltage Regulator Module, QFN-FCMOD7; Manufacturer: Texas Instruments; Nominal Supply Current: 120-400uA; SizeZ_mm: 2.1mm; AEC Qualified: No; Output Type: AdjustableProgrammable; Switching Topology: Buck; AEC Grade: NA; Standoff Height: 0mm; Max Supply Voltage: 16V; Number Of Outputs: 1; Switching Frequency: 1400/2000kHz; TJmax_C: +125°C; Max Duty Cycle: 98%; Output Voltage: 0.6-7V

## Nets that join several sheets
PGND: PMP23537A_Controller (53 pins), PMP23537A_PFC (51 pins)
3V3: PMP23537A_Controller (6 pins), PMP23537A_PFC (10 pins)
5Vp: PMP23537A_Controller (9 pins), PMP23537A_PFC (12 pins)
5Vs: PMP23537A_Controller (J302.4), PMP23537A_PFC (C129.1 C142.1 U104.1)
12V1: PMP23537A_Controller (J303.1), PMP23537A_PFC (C122.2 C131.1 U102.11 U102.16)
12Vp: PMP23537A_Controller (12Vp.1 J303.4), PMP23537A_PFC (11 pins)
AC_CUR_SENSE: PMP23537A_Controller (R312.2), PMP23537A_PFC (U100.6)
ACL_SENSE: PMP23537A_Controller (C314.1 J301.12 R329.2), PMP23537A_PFC (R101.1)
ACN_SENSE: PMP23537A_Controller (C313.1 J301.17 R328.2), PMP23537A_PFC (R105.1)
AINN: PMP23537A_Controller (J302.2 J302.3), PMP23537A_PFC (7 pins)
BB_ONOFF: PMP23537A_Controller (J301.60), PMP23537A_PFC (R139.1)
BBFET: PMP23537A_Controller (J301.54), PMP23537A_PFC (R144.1)
CLKIN: PMP23537A_Controller (C307.1 J301.70 J301.74 R317.1), PMP23537A_PFC (R117.2)
DOUT: PMP23537A_Controller (R318.2), PMP23537A_PFC (R118.2)
HFFET_HS: PMP23537A_Controller (U301#1.4), PMP23537A_PFC (J100.8)
HFFET_LS: PMP23537A_Controller (U303#1.4), PMP23537A_PFC (J100.1)
HS_ZCD: PMP23537A_Controller (C302.1 J301.50), PMP23537A_PFC (HS_ZCD.1 J100.4)
LFFET_HS: PMP23537A_Controller (J301.49), PMP23537A_PFC (R136.1)
LFFET_LS: PMP23537A_Controller (J301.51), PMP23537A_PFC (R134.1)
LS_ZCD: PMP23537A_Controller (C316.1 J301.52), PMP23537A_PFC (J100.5 LS_ZCD.1)
RELAY_CTRL: PMP23537A_Controller (J301.58), PMP23537A_PFC (R137.1)
VBB: PMP23537A_Controller (R354.2), PMP23537A_PFC (7 pins)
Vbulk: PMP23537A_Controller (J303.2 J303.5 R350.2), PMP23537A_PFC (18 pins)
ZCD: PMP23537A_Controller (R303.1 R314.1), PMP23537A_PFC (13 pins)

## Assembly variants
001: not fitted C147 C307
